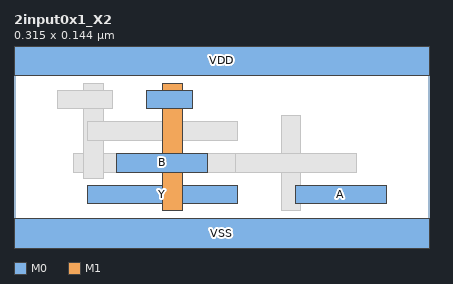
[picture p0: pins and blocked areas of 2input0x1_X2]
MACRO 2input0x1_X2
  CLASS CORE ;
  ORIGIN 0 0 ;
  FOREIGN 2input0x1_X2 0 0 ;
  SIZE 0.3150 BY 0.1440 ;
  SYMMETRY X Y ;
  SITE coresite ;
  PIN A
    DIRECTION INPUT ;
    USE SIGNAL ;
    PORT
      LAYER M0 ;
        RECT 0.2130 0.0290 0.2820 0.0430 ;
    END
  END A
  PIN B
    DIRECTION INPUT ;
    USE SIGNAL ;
    PORT
      LAYER M0 ;
        RECT 0.0780 0.0530 0.1470 0.0670 ;
    END
  END B
  PIN Y
    DIRECTION OUTPUT ;
    USE SIGNAL ;
    PORT
      LAYER M1 ;
        RECT 0.1125 0.0240 0.1275 0.1200 ;
      LAYER M0 ;
        RECT 0.1005 0.1010 0.1350 0.1150 ;
        RECT 0.0555 0.0290 0.1695 0.0430 ;
    END
  END Y
  PIN VDD
    DIRECTION INOUT ;
    USE POWER ;
    SHAPE ABUTMENT ;
    PORT
      LAYER M0 ;
        RECT 0.0000 0.1260 0.3150 0.1620 ;
    END
  END VDD
  PIN VSS
    DIRECTION INOUT ;
    USE GROUND ;
    SHAPE ABUTMENT ;
    PORT
      LAYER M0 ;
        RECT 0.0000 -0.0180 0.3150 0.0180 ;
    END
  END VSS
  OBS
    LAYER M2 ;
      RECT 0.0450 0.0530 0.2250 0.0670 ;
    LAYER V1 ;
      RECT 0.0530 0.0530 0.0670 0.0670 ;
      RECT 0.2030 0.0530 0.2170 0.0670 ;
    LAYER M1 ;
      RECT 0.2025 0.0240 0.2175 0.0960 ;
      RECT 0.0525 0.0480 0.0675 0.1200 ;
    LAYER V0 ;
      RECT 0.1130 0.1010 0.1270 0.1150 ;
      RECT 0.1130 0.0290 0.1270 0.0430 ;
      RECT 0.0530 0.1010 0.0670 0.1150 ;
      RECT 0.2030 0.0530 0.2170 0.0670 ;
    LAYER M0 ;
      RECT 0.1680 0.0530 0.2595 0.0670 ;
      RECT 0.0555 0.0770 0.1695 0.0910 ;
      RECT 0.0330 0.1010 0.0750 0.1150 ;
  END
END 2input0x1_X2
